VERSION 5.7 ;
  NOWIREEXTENSIONATPIN ON ;
  DIVIDERCHAR "/" ;
  BUSBITCHARS "[]" ;
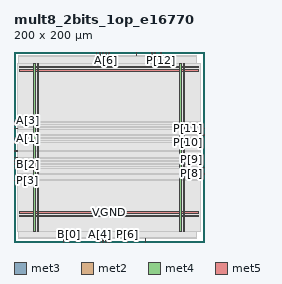
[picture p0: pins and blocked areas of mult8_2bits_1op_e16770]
MACRO mult8_2bits_1op_e16770
  CLASS BLOCK ;
  FOREIGN mult8_2bits_1op_e16770 ;
  ORIGIN 0.000 0.000 ;
  SIZE 200.000 BY 200.000 ;
  PIN A[0]
    DIRECTION INPUT ;
    USE SIGNAL ;
    ANTENNAGATEAREA 0.495000 ;
    PORT
      LAYER met3 ;
        RECT 0.000 105.440 4.000 106.040 ;
    END
  END A[0]
  PIN A[1]
    DIRECTION INPUT ;
    USE SIGNAL ;
    ANTENNAGATEAREA 0.213000 ;
    PORT
      LAYER met3 ;
        RECT 0.000 108.840 4.000 109.440 ;
    END
  END A[1]
  PIN A[2]
    DIRECTION INPUT ;
    USE SIGNAL ;
    ANTENNAGATEAREA 0.196500 ;
    PORT
      LAYER met3 ;
        RECT 0.000 122.440 4.000 123.040 ;
    END
  END A[2]
  PIN A[3]
    DIRECTION INPUT ;
    USE SIGNAL ;
    ANTENNAGATEAREA 0.213000 ;
    PORT
      LAYER met3 ;
        RECT 0.000 119.040 4.000 119.640 ;
    END
  END A[3]
  PIN A[4]
    DIRECTION INPUT ;
    USE SIGNAL ;
    ANTENNAGATEAREA 0.196500 ;
    PORT
      LAYER met2 ;
        RECT 90.250 0.000 90.530 4.000 ;
    END
  END A[4]
  PIN A[5]
    DIRECTION INPUT ;
    USE SIGNAL ;
    ANTENNAGATEAREA 0.159000 ;
    PORT
      LAYER met2 ;
        RECT 93.470 0.000 93.750 4.000 ;
    END
  END A[5]
  PIN A[6]
    DIRECTION INPUT ;
    USE SIGNAL ;
    ANTENNAGATEAREA 0.196500 ;
    PORT
      LAYER met2 ;
        RECT 96.690 196.000 96.970 200.000 ;
    END
  END A[6]
  PIN A[7]
    DIRECTION INPUT ;
    USE SIGNAL ;
    ANTENNAGATEAREA 0.159000 ;
    PORT
      LAYER met2 ;
        RECT 93.470 196.000 93.750 200.000 ;
    END
  END A[7]
  PIN B[0]
    DIRECTION INPUT ;
    USE SIGNAL ;
    ANTENNAGATEAREA 0.213000 ;
    PORT
      LAYER met2 ;
        RECT 58.050 0.000 58.330 4.000 ;
    END
  END B[0]
  PIN B[1]
    DIRECTION INPUT ;
    USE SIGNAL ;
    ANTENNAGATEAREA 0.213000 ;
    PORT
      LAYER met3 ;
        RECT 0.000 78.240 4.000 78.840 ;
    END
  END B[1]
  PIN B[2]
    DIRECTION INPUT ;
    USE SIGNAL ;
    ANTENNAGATEAREA 0.213000 ;
    PORT
      LAYER met3 ;
        RECT 0.000 81.640 4.000 82.240 ;
    END
  END B[2]
  PIN B[3]
    DIRECTION INPUT ;
    USE SIGNAL ;
    ANTENNAGATEAREA 0.495000 ;
    PORT
      LAYER met2 ;
        RECT 51.610 0.000 51.890 4.000 ;
    END
  END B[3]
  PIN B[4]
    DIRECTION INPUT ;
    USE SIGNAL ;
    ANTENNAGATEAREA 0.159000 ;
    PORT
      LAYER met3 ;
        RECT 0.000 125.840 4.000 126.440 ;
    END
  END B[4]
  PIN B[5]
    DIRECTION INPUT ;
    USE SIGNAL ;
    ANTENNAGATEAREA 0.126000 ;
    PORT
      LAYER met2 ;
        RECT 99.910 196.000 100.190 200.000 ;
    END
  END B[5]
  PIN B[6]
    DIRECTION INPUT ;
    USE SIGNAL ;
    ANTENNAGATEAREA 0.159000 ;
    PORT
      LAYER met2 ;
        RECT 90.250 196.000 90.530 200.000 ;
    END
  END B[6]
  PIN B[7]
    DIRECTION INPUT ;
    USE SIGNAL ;
    ANTENNAGATEAREA 0.196500 ;
    PORT
      LAYER met2 ;
        RECT 87.030 196.000 87.310 200.000 ;
    END
  END B[7]
  PIN P[0]
    DIRECTION OUTPUT ;
    USE SIGNAL ;
    ANTENNADIFFAREA 0.445500 ;
    PORT
      LAYER met3 ;
        RECT 0.000 88.440 4.000 89.040 ;
    END
  END P[0]
  PIN P[10]
    DIRECTION OUTPUT ;
    USE SIGNAL ;
    ANTENNADIFFAREA 1.336500 ;
    PORT
      LAYER met3 ;
        RECT 196.000 112.240 200.000 112.840 ;
    END
  END P[10]
  PIN P[11]
    DIRECTION OUTPUT ;
    USE SIGNAL ;
    ANTENNADIFFAREA 1.336500 ;
    PORT
      LAYER met3 ;
        RECT 196.000 119.040 200.000 119.640 ;
    END
  END P[11]
  PIN P[12]
    DIRECTION OUTPUT ;
    USE SIGNAL ;
    ANTENNADIFFAREA 1.336500 ;
    PORT
      LAYER met2 ;
        RECT 154.650 196.000 154.930 200.000 ;
    END
  END P[12]
  PIN P[13]
    DIRECTION OUTPUT ;
    USE SIGNAL ;
    ANTENNADIFFAREA 1.336500 ;
    PORT
      LAYER met2 ;
        RECT 144.990 196.000 145.270 200.000 ;
    END
  END P[13]
  PIN P[14]
    DIRECTION OUTPUT ;
    USE SIGNAL ;
    ANTENNADIFFAREA 1.336500 ;
    PORT
      LAYER met2 ;
        RECT 148.210 196.000 148.490 200.000 ;
    END
  END P[14]
  PIN P[15]
    DIRECTION OUTPUT ;
    USE SIGNAL ;
    ANTENNADIFFAREA 1.782000 ;
    PORT
      LAYER met2 ;
        RECT 128.890 196.000 129.170 200.000 ;
    END
  END P[15]
  PIN P[1]
    DIRECTION OUTPUT ;
    USE SIGNAL ;
    ANTENNADIFFAREA 0.445500 ;
    PORT
      LAYER met3 ;
        RECT 0.000 85.040 4.000 85.640 ;
    END
  END P[1]
  PIN P[2]
    DIRECTION OUTPUT ;
    USE SIGNAL ;
    ANTENNADIFFAREA 0.445500 ;
    PORT
      LAYER met3 ;
        RECT 0.000 95.240 4.000 95.840 ;
    END
  END P[2]
  PIN P[3]
    DIRECTION OUTPUT ;
    USE SIGNAL ;
    ANTENNADIFFAREA 0.445500 ;
    PORT
      LAYER met3 ;
        RECT 0.000 64.640 4.000 65.240 ;
    END
  END P[3]
  PIN P[4]
    DIRECTION OUTPUT ;
    USE SIGNAL ;
    ANTENNADIFFAREA 0.445500 ;
    PORT
      LAYER met2 ;
        RECT 96.690 0.000 96.970 4.000 ;
    END
  END P[4]
  PIN P[5]
    DIRECTION OUTPUT ;
    USE SIGNAL ;
    ANTENNADIFFAREA 0.445500 ;
    PORT
      LAYER met2 ;
        RECT 99.910 0.000 100.190 4.000 ;
    END
  END P[5]
  PIN P[6]
    DIRECTION OUTPUT ;
    USE SIGNAL ;
    ANTENNADIFFAREA 0.891000 ;
    PORT
      LAYER met2 ;
        RECT 119.230 0.000 119.510 4.000 ;
    END
  END P[6]
  PIN P[7]
    DIRECTION OUTPUT ;
    USE SIGNAL ;
    ANTENNADIFFAREA 0.891000 ;
    PORT
      LAYER met2 ;
        RECT 138.550 0.000 138.830 4.000 ;
    END
  END P[7]
  PIN P[8]
    DIRECTION OUTPUT ;
    USE SIGNAL ;
    ANTENNADIFFAREA 1.336500 ;
    PORT
      LAYER met3 ;
        RECT 196.000 71.440 200.000 72.040 ;
    END
  END P[8]
  PIN P[9]
    DIRECTION OUTPUT ;
    USE SIGNAL ;
    ANTENNADIFFAREA 0.891000 ;
    PORT
      LAYER met3 ;
        RECT 196.000 78.240 200.000 78.840 ;
    END
  END P[9]
  PIN VGND
    DIRECTION INOUT ;
    USE GROUND ;
    PORT
      LAYER met4 ;
        RECT 24.340 10.640 25.940 187.920 ;
    END
    PORT
      LAYER met4 ;
        RECT 177.940 10.640 179.540 187.920 ;
    END
    PORT
      LAYER met5 ;
        RECT 5.280 30.030 194.360 31.630 ;
    END
    PORT
      LAYER met5 ;
        RECT 5.280 183.210 194.360 184.810 ;
    END
  END VGND
  PIN VPWR
    DIRECTION INOUT ;
    USE POWER ;
    PORT
      LAYER met4 ;
        RECT 21.040 10.640 22.640 187.920 ;
    END
    PORT
      LAYER met4 ;
        RECT 174.640 10.640 176.240 187.920 ;
    END
    PORT
      LAYER met5 ;
        RECT 5.280 26.730 194.360 28.330 ;
    END
    PORT
      LAYER met5 ;
        RECT 5.280 179.910 194.360 181.510 ;
    END
  END VPWR
  OBS
      LAYER nwell ;
        RECT 5.330 10.795 194.310 187.870 ;
      LAYER li1 ;
        RECT 5.520 10.795 194.120 187.765 ;
      LAYER met1 ;
        RECT 4.210 10.640 194.120 187.920 ;
      LAYER met2 ;
        RECT 4.230 195.720 86.750 196.250 ;
        RECT 87.590 195.720 89.970 196.250 ;
        RECT 90.810 195.720 93.190 196.250 ;
        RECT 94.030 195.720 96.410 196.250 ;
        RECT 97.250 195.720 99.630 196.250 ;
        RECT 100.470 195.720 128.610 196.250 ;
        RECT 129.450 195.720 144.710 196.250 ;
        RECT 145.550 195.720 147.930 196.250 ;
        RECT 148.770 195.720 154.370 196.250 ;
        RECT 155.210 195.720 192.190 196.250 ;
        RECT 4.230 4.280 192.190 195.720 ;
        RECT 4.230 4.000 51.330 4.280 ;
        RECT 52.170 4.000 57.770 4.280 ;
        RECT 58.610 4.000 89.970 4.280 ;
        RECT 90.810 4.000 93.190 4.280 ;
        RECT 94.030 4.000 96.410 4.280 ;
        RECT 97.250 4.000 99.630 4.280 ;
        RECT 100.470 4.000 118.950 4.280 ;
        RECT 119.790 4.000 138.270 4.280 ;
        RECT 139.110 4.000 192.190 4.280 ;
      LAYER met3 ;
        RECT 3.990 126.840 196.000 187.845 ;
        RECT 4.400 125.440 196.000 126.840 ;
        RECT 3.990 123.440 196.000 125.440 ;
        RECT 4.400 122.040 196.000 123.440 ;
        RECT 3.990 120.040 196.000 122.040 ;
        RECT 4.400 118.640 195.600 120.040 ;
        RECT 3.990 113.240 196.000 118.640 ;
        RECT 3.990 111.840 195.600 113.240 ;
        RECT 3.990 109.840 196.000 111.840 ;
        RECT 4.400 108.440 196.000 109.840 ;
        RECT 3.990 106.440 196.000 108.440 ;
        RECT 4.400 105.040 196.000 106.440 ;
        RECT 3.990 96.240 196.000 105.040 ;
        RECT 4.400 94.840 196.000 96.240 ;
        RECT 3.990 89.440 196.000 94.840 ;
        RECT 4.400 88.040 196.000 89.440 ;
        RECT 3.990 86.040 196.000 88.040 ;
        RECT 4.400 84.640 196.000 86.040 ;
        RECT 3.990 82.640 196.000 84.640 ;
        RECT 4.400 81.240 196.000 82.640 ;
        RECT 3.990 79.240 196.000 81.240 ;
        RECT 4.400 77.840 195.600 79.240 ;
        RECT 3.990 72.440 196.000 77.840 ;
        RECT 3.990 71.040 195.600 72.440 ;
        RECT 3.990 65.640 196.000 71.040 ;
        RECT 4.400 64.240 196.000 65.640 ;
        RECT 3.990 10.715 196.000 64.240 ;
  END
END mult8_2bits_1op_e16770
END LIBRARY

